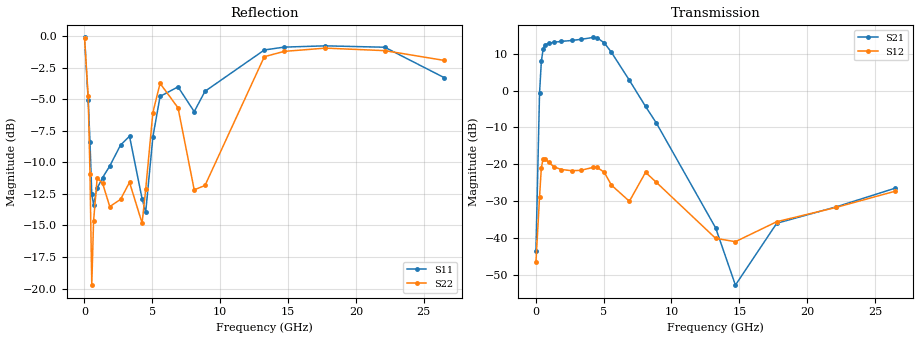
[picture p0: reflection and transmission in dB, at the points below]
!Agilent Technologies,N5242A,MY52422126,A.09.90.01
!Agilent N5242A: A.09.90.01
!Date: Thursday, November 19, 2015 09:13:52
!Correction: S11(Full 2 Port(1,2))
!S21(Full 2 Port(1,2))
!S12(Full 2 Port(1,2))
!S22(Full 2 Port(1,2))
!S2P File: Measurements: S11, S21, S12, S22:
# Hz S  dB  R 50
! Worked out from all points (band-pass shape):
!   201 points, 10 MHz to 26.5 GHz, reference 50 ohm
!   highest |S21| = 14.43 dB at 4.248 GHz (marker M1); lowest = -52.7 dB at 14.71 GHz (marker M2)
!   |S21| within 3 dB of the highest: 565.3 MHz to 5.373 GHz (4.808 GHz wide, 162 % of centre)
!   lowest |S11| = -14.0 dB at 4.513 GHz (marker M3), VSWR 1.50, Z = 33.3 - j0.123 ohm
!   |S11| at or under -10 dB: 458.9 MHz to 1.996 GHz (1.538 GHz wide, 125 % of centre); 3.918 GHz to 4.86 GHz (941.8 MHz wide, 21.5 % of centre)
!   |S22| runs from -19.7 to -0.2 dB; largest |S21 - S12| = 5.3
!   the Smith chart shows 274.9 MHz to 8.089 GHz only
!   S11 on the Smith chart (normalised r, x): 274.9 MHz: 0.29, +0.13; 539.8 MHz: 1.55, +0.26; 3.321 GHz: 0.43, +0.03; 6.897 GHz: 0.61, +1.21; 8.089 GHz: 2.33, -1.17
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1e7  -0.11 -11.3  -43.42 27.3  -46.54 49.5  -0.19 -9.1
2.749e8  -5.08 163.5  -0.75 -31.2  -28.92 146.3  -4.79 -173.2
4.0735e8  -8.38 94.3  7.91 -76.0  -20.88 91.3  -10.89 116.0
5.398e8  -12.53 19.3  11.22 -117.0  -18.54 46.7  -19.73 -5.1
6.7225e8  -13.36 -44.8  12.31 -146.8  -18.43 16.8  -14.63 -88.7
9.3715e8  -12.06 -103.1  12.84 173.8  -19.40 -18.9  -11.26 -137.7
1.3345e9  -11.22 -131.5  13.10 133.3  -20.65 -49.5  -11.66 -166.2
1.8643e9  -10.30 -145.1  13.34 89.5  -21.40 -79.2  -13.51 -177.5
2.659e9  -8.64 -163.2  13.60 30.6  -21.72 -118.5  -12.94 -178.8
3.32125e9  -7.94 176.2  13.90 -19.0  -21.62 -151.9  -11.59 157.2
4.2484e9  -12.89 159.5  14.43 -94.7  -20.80 153.0  -14.82 40.5
4.5133e9  -13.96 -179.5  14.32 -119.7  -20.81 133.1  -12.15 -16.6
5.0431e9  -8.00 -169.3  12.96 -171.6  -22.15 89.0  -6.06 -88.2
5.5729e9  -4.78 162.7  10.39 141.0  -25.63 45.5  -3.75 -135.0
6.8974e9  -4.03 70.8  2.80 39.8  -30.01 120.2  -5.69 142.8
8.08945e9  -5.99 -22.0  -4.31 -32.4  -22.16 12.3  -12.18 66.2
8.88415e9  -4.38 -67.8  -8.79 -82.1  -24.88 -54.9  -11.84 -30.1
1.3255e10  -1.11 179.3  -37.24 137.0  -40.07 -130.9  -1.64 -175.5
1.471195e10  -0.88 161.0  -52.75 108.9  -40.97 -140.7  -1.22 164.5
1.77583e10  -0.78 131.1  -35.97 -178.7  -35.55 -177.7  -0.96 131.9
2.212915e10  -0.89 93.2  -31.54 50.3  -31.68 52.0  -1.16 95.5
2.65e10  -3.29 68.1  -26.45 -100.4  -27.27 -92.4  -1.93 67.7
